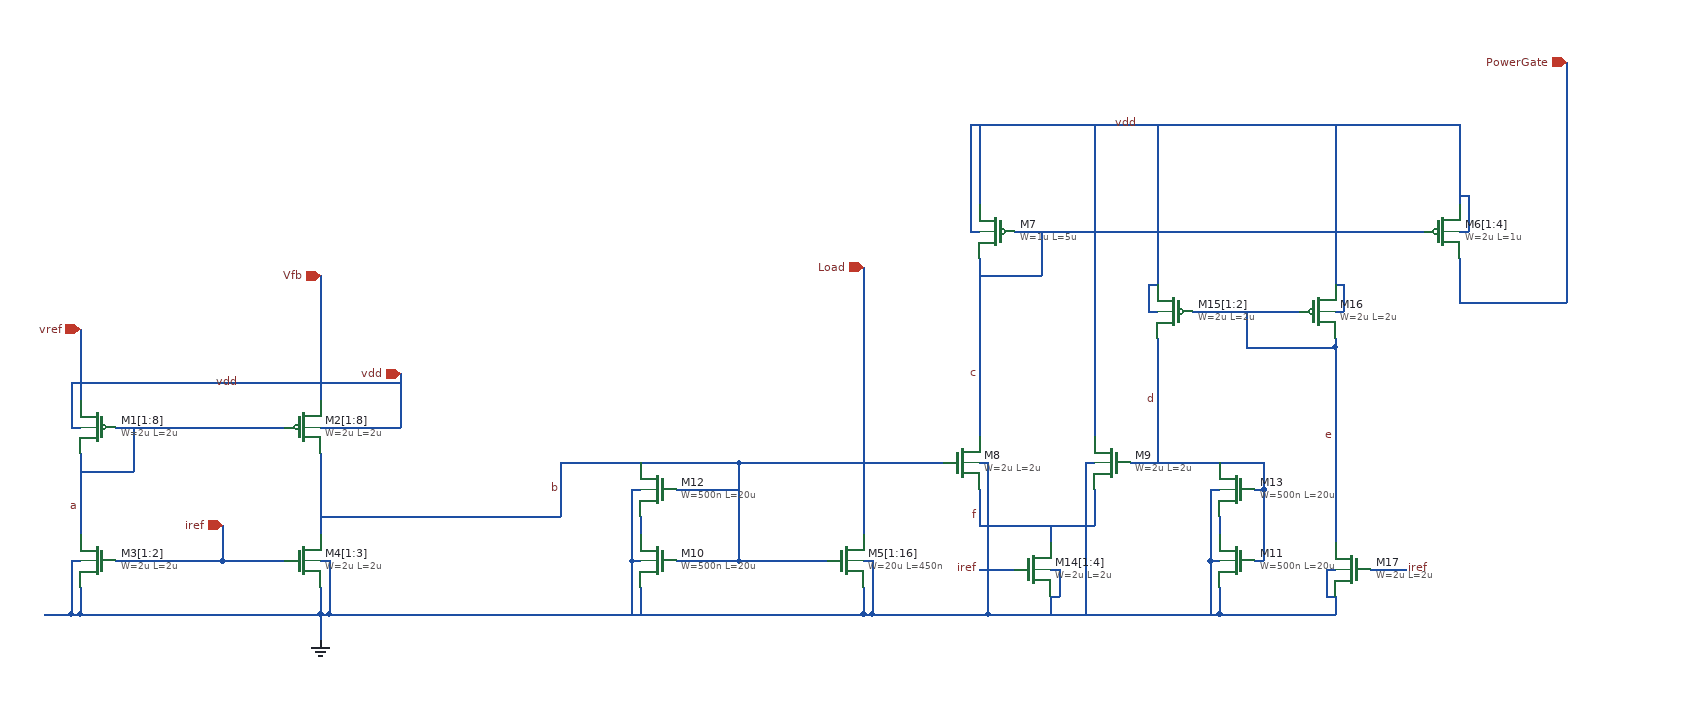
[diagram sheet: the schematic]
v {xschem version=3.4.5 file_version=1.2
}
G {}
K {}
V {}
S {}
E {}
N 370 -150 370 -120 {
lab=GND}
N 370 -180 380 -180 {
lab=GND}
N 380 -180 380 -120 {
lab=GND}
N 370 -120 380 -120 {
lab=GND}
N 370 -120 370 -90 {
lab=GND}
N 980 -150 980 -120 {
lab=GND}
N 980 -330 980 -210 {
lab=Load}
N 980 -180 990 -180 {
lab=GND}
N 990 -180 990 -120 {
lab=GND}
N 980 -120 990 -120 {
lab=GND}
N 980 -510 980 -330 {
lab=Load}
N 880 -120 980 -120 {
lab=GND}
N 840 -180 940 -180 {
lab=b}
N 840 -250 840 -180 {
lab=b}
N 260 -220 260 -180 {
lab=iref}
N 370 -250 370 -210 {
lab=b}
N 370 -300 370 -250 {
lab=b}
N 370 -330 380 -330 {
lab=vdd}
N 380 -330 460 -330 {
lab=vdd}
N 260 -180 330 -180 {
lab=iref}
N 100 -150 100 -120 {
lab=GND}
N 90 -180 100 -180 {
lab=GND}
N 90 -180 90 -120 {
lab=GND}
N 90 -120 100 -120 {
lab=GND}
N 100 -250 100 -210 {
lab=a}
N 100 -300 100 -250 {
lab=a}
N 90 -330 100 -330 {
lab=vdd}
N 140 -330 330 -330 {
lab=a}
N 140 -180 260 -180 {
lab=iref}
N 100 -120 370 -120 {
lab=GND}
N 90 -380 90 -330 {
lab=vdd}
N 90 -380 460 -380 {
lab=vdd}
N 100 -280 160 -280 {
lab=a}
N 160 -330 160 -280 {
lab=a}
N 460 -390 460 -330 {
lab=vdd}
N 370 -500 370 -360 {
lab=Vfb}
N 1770 -740 1770 -520 {
lab=PowerGate}
N 380 -120 880 -120 {
lab=GND}
N 1650 -550 1660 -550 {
lab=vdd}
N 1110 -290 1120 -290 {
lab=f}
N 1100 -550 1110 -550 {
lab=vdd}
N 1100 -600 1100 -550 {
lab=vdd}
N 1650 -600 1650 -580 {
lab=vdd}
N 1770 -520 1770 -470 {
lab=PowerGate}
N 1110 -520 1110 -430 {
lab=c}
N 1110 -610 1110 -580 {
lab=vdd}
N 1100 -670 1100 -600 {
lab=vdd}
N 1370 -670 1650 -670 {
lab=vdd}
N 1650 -670 1650 -600 {
lab=vdd}
N 1660 -590 1660 -550 {
lab=vdd}
N 1650 -590 1660 -590 {
lab=vdd}
N 990 -120 1110 -120 {
lab=GND}
N 1110 -120 1120 -120 {
lab=GND}
N 1110 -430 1110 -360 {
lab=c}
N 1120 -120 1310 -120 {
lab=GND}
N 1190 -140 1190 -120 {
lab=GND}
N 1110 -670 1110 -610 {
lab=vdd}
N 720 -180 730 -180 {
lab=GND}
N 720 -180 720 -120 {
lab=GND}
N 730 -150 730 -120 {
lab=GND}
N 770 -180 840 -180 {
lab=b}
N 730 -230 730 -210 {
lab=#net1}
N 720 -260 720 -180 {
lab=GND}
N 720 -260 730 -260 {
lab=GND}
N 730 -290 840 -290 {
lab=b}
N 840 -290 840 -250 {
lab=b}
N 770 -260 840 -260 {
lab=b}
N 840 -290 1050 -290 {
lab=b}
N 370 -230 640 -230 {
lab=b}
N 640 -290 640 -230 {
lab=b}
N 640 -290 730 -290 {
lab=b}
N 1650 -520 1650 -480 {
lab=PowerGate}
N 1650 -480 1650 -470 {
lab=PowerGate}
N 1650 -470 1770 -470 {
lab=PowerGate}
N 1110 -500 1180 -500 {
lab=c}
N 1180 -550 1180 -500 {
lab=c}
N 1120 -290 1120 -260 {
lab=f}
N 1050 -290 1070 -290 {
lab=b}
N 1110 -360 1110 -320 {
lab=c}
N 1190 -220 1190 -200 {
lab=f}
N 1110 -220 1140 -220 {
lab=f}
N 1110 -260 1110 -220 {
lab=f}
N 1230 -290 1240 -290 {
lab=f}
N 1230 -290 1230 -260 {
lab=f}
N 1240 -360 1240 -320 {
lab=vdd}
N 1240 -260 1240 -220 {
lab=f}
N 1140 -220 1240 -220 {
lab=f}
N 1240 -670 1240 -360 {
lab=vdd}
N 1370 -180 1380 -180 {
lab=GND}
N 1370 -180 1370 -120 {
lab=GND}
N 1380 -150 1380 -120 {
lab=GND}
N 1380 -230 1380 -210 {
lab=#net2}
N 1370 -260 1370 -180 {
lab=GND}
N 1370 -260 1380 -260 {
lab=GND}
N 1310 -120 1380 -120 {
lab=GND}
N 1420 -180 1430 -180 {
lab=d}
N 1430 -260 1430 -180 {
lab=d}
N 1420 -260 1430 -260 {
lab=d}
N 1420 -260 1430 -260 {
lab=d}
N 1430 -290 1430 -260 {
lab=d}
N 1280 -290 1430 -290 {
lab=d}
N 1310 -360 1310 -290 {
lab=d}
N 1190 -170 1200 -170 {
lab=GND}
N 1200 -170 1200 -140 {
lab=GND}
N 1190 -140 1200 -140 {
lab=GND}
N 1110 -170 1150 -170 {
lab=iref}
N 1100 -670 1370 -670 {
lab=vdd}
N 1150 -550 1610 -550 {
lab=c}
N 1310 -430 1310 -360 {
lab=d}
N 1350 -460 1470 -460 {
lab=e}
N 1300 -460 1310 -460 {
lab=vdd}
N 1300 -490 1300 -460 {
lab=vdd}
N 1300 -490 1310 -490 {
lab=vdd}
N 1310 -670 1310 -490 {
lab=vdd}
N 1510 -670 1510 -490 {
lab=vdd}
N 1510 -460 1520 -460 {
lab=vdd}
N 1520 -490 1520 -460 {
lab=vdd}
N 1510 -490 1520 -490 {
lab=vdd}
N 1410 -460 1410 -420 {
lab=e}
N 1410 -420 1510 -420 {
lab=e}
N 1510 -430 1510 -420 {
lab=e}
N 1510 -140 1510 -120 {
lab=GND}
N 1500 -170 1510 -170 {
lab=GND}
N 1500 -170 1500 -140 {
lab=GND}
N 1500 -140 1510 -140 {
lab=GND}
N 1550 -170 1590 -170 {
lab=iref}
N 1380 -120 1510 -120 {
lab=GND}
N 1510 -420 1510 -200 {
lab=e}
N 60 -120 90 -120 {
lab=GND}
N 100 -440 100 -360 {
lab=vref}
N 1120 -260 1120 -120 {}
N 1230 -260 1230 -120 {}
C {symbols/pfet_03v3.sym} 350 -330 0 0 {name=M2[1:8]
L=2u
W=2u
nf=1
m=1
ad="'int((nf+1)/2) * W/nf * 0.18u'"
pd="'2*int((nf+1)/2) * (W/nf + 0.18u)'"
as="'int((nf+2)/2) * W/nf * 0.18u'"
ps="'2*int((nf+2)/2) * (W/nf + 0.18u)'"
nrd="'0.18u / W'" nrs="'0.18u / W'"
sa=0 sb=0 sd=0
model=pfet_03v3
spiceprefix=X
}
C {symbols/nfet_03v3.sym} 350 -180 0 0 {name=M4[1:3]
L=2u
W=2u
nf=1
m=1
ad="'int((nf+1)/2) * W/nf * 0.18u'"
pd="'2*int((nf+1)/2) * (W/nf + 0.18u)'"
as="'int((nf+2)/2) * W/nf * 0.18u'"
ps="'2*int((nf+2)/2) * (W/nf + 0.18u)'"
nrd="'0.18u / W'" nrs="'0.18u / W'"
sa=0 sb=0 sd=0
model=nfet_03v3
spiceprefix=X
}
C {devices/gnd.sym} 370 -90 0 0 {name=l1 lab=GND}
C {devices/iopin.sym} 100 -440 3 0 {name=p3 lab=vref
}
C {devices/iopin.sym} 260 -220 2 0 {name=p4 lab=iref
}
C {devices/iopin.sym} 460 -390 3 0 {name=p5 lab=vdd
}
C {devices/iopin.sym} 980 -510 3 0 {name=p1 lab=Load
}
C {symbols/nfet_03v3.sym} 960 -180 0 0 {name=M5[1:16]
L=450n
W=20u
nf=1
m=1
ad="'int((nf+1)/2) * W/nf * 0.18u'"
pd="'2*int((nf+1)/2) * (W/nf + 0.18u)'"
as="'int((nf+2)/2) * W/nf * 0.18u'"
ps="'2*int((nf+2)/2) * (W/nf + 0.18u)'"
nrd="'0.18u / W'" nrs="'0.18u / W'"
sa=0 sb=0 sd=0
model=nfet_03v3
spiceprefix=X
}
C {symbols/pfet_03v3.sym} 120 -330 0 1 {name=M1[1:8]
L=2u
W=2u
nf=1
m=1
ad="'int((nf+1)/2) * W/nf * 0.18u'"
pd="'2*int((nf+1)/2) * (W/nf + 0.18u)'"
as="'int((nf+2)/2) * W/nf * 0.18u'"
ps="'2*int((nf+2)/2) * (W/nf + 0.18u)'"
nrd="'0.18u / W'" nrs="'0.18u / W'"
sa=0 sb=0 sd=0
model=pfet_03v3
spiceprefix=X
}
C {symbols/nfet_03v3.sym} 120 -180 0 1 {name=M3[1:2]
L=2u
W=2u
nf=1
m=1
ad="'int((nf+1)/2) * W/nf * 0.18u'"
pd="'2*int((nf+1)/2) * (W/nf + 0.18u)'"
as="'int((nf+2)/2) * W/nf * 0.18u'"
ps="'2*int((nf+2)/2) * (W/nf + 0.18u)'"
nrd="'0.18u / W'" nrs="'0.18u / W'"
sa=0 sb=0 sd=0
model=nfet_03v3
spiceprefix=X
}
C {devices/iopin.sym} 370 -500 3 0 {name=p2 lab=Vfb
}
C {devices/iopin.sym} 1770 -740 3 0 {name=p6 lab=PowerGate
}
C {devices/lab_wire.sym} 280 -380 0 0 {name=p7 sig_type=std_logic lab=vdd}
C {symbols/pfet_03v3.sym} 1630 -550 0 0 {name=M6[1:4]
L=1u
W=2u
nf=1
m=1
ad="'int((nf+1)/2) * W/nf * 0.18u'"
pd="'2*int((nf+1)/2) * (W/nf + 0.18u)'"
as="'int((nf+2)/2) * W/nf * 0.18u'"
ps="'2*int((nf+2)/2) * (W/nf + 0.18u)'"
nrd="'0.18u / W'" nrs="'0.18u / W'"
sa=0 sb=0 sd=0
model=pfet_03v3
spiceprefix=X
}
C {symbols/pfet_03v3.sym} 1130 -550 0 1 {name=M7
L=5u
W=1u
nf=1
m=1
ad="'int((nf+1)/2) * W/nf * 0.18u'"
pd="'2*int((nf+1)/2) * (W/nf + 0.18u)'"
as="'int((nf+2)/2) * W/nf * 0.18u'"
ps="'2*int((nf+2)/2) * (W/nf + 0.18u)'"
nrd="'0.18u / W'" nrs="'0.18u / W'"
sa=0 sb=0 sd=0
model=pfet_03v3
spiceprefix=X
}
C {symbols/nfet_03v3.sym} 1090 -290 0 0 {name=M8
L=2u
W=2u
nf=1
m=1
ad="'int((nf+1)/2) * W/nf * 0.18u'"
pd="'2*int((nf+1)/2) * (W/nf + 0.18u)'"
as="'int((nf+2)/2) * W/nf * 0.18u'"
ps="'2*int((nf+2)/2) * (W/nf + 0.18u)'"
nrd="'0.18u / W'" nrs="'0.18u / W'"
sa=0 sb=0 sd=0
model=nfet_03v3
spiceprefix=X
}
C {devices/lab_wire.sym} 1290 -670 0 0 {name=p8 sig_type=std_logic lab=vdd}
C {symbols/nfet_03v3.sym} 750 -180 0 1 {name=M10
L=20u
W=500n
nf=1
m=1
ad="'int((nf+1)/2) * W/nf * 0.18u'"
pd="'2*int((nf+1)/2) * (W/nf + 0.18u)'"
as="'int((nf+2)/2) * W/nf * 0.18u'"
ps="'2*int((nf+2)/2) * (W/nf + 0.18u)'"
nrd="'0.18u / W'" nrs="'0.18u / W'"
sa=0 sb=0 sd=0
model=nfet_03v3
spiceprefix=X
}
C {symbols/nfet_03v3.sym} 750 -260 0 1 {name=M12
L=20u
W=500n
nf=1
m=1
ad="'int((nf+1)/2) * W/nf * 0.18u'"
pd="'2*int((nf+1)/2) * (W/nf + 0.18u)'"
as="'int((nf+2)/2) * W/nf * 0.18u'"
ps="'2*int((nf+2)/2) * (W/nf + 0.18u)'"
nrd="'0.18u / W'" nrs="'0.18u / W'"
sa=0 sb=0 sd=0
model=nfet_03v3
spiceprefix=X
}
C {symbols/nfet_03v3.sym} 1260 -290 0 1 {name=M9
L=2u
W=2u
nf=1
m=1
ad="'int((nf+1)/2) * W/nf * 0.18u'"
pd="'2*int((nf+1)/2) * (W/nf + 0.18u)'"
as="'int((nf+2)/2) * W/nf * 0.18u'"
ps="'2*int((nf+2)/2) * (W/nf + 0.18u)'"
nrd="'0.18u / W'" nrs="'0.18u / W'"
sa=0 sb=0 sd=0
model=nfet_03v3
spiceprefix=X
}
C {symbols/nfet_03v3.sym} 1400 -180 0 1 {name=M11
L=20u
W=500n
nf=1
m=1
ad="'int((nf+1)/2) * W/nf * 0.18u'"
pd="'2*int((nf+1)/2) * (W/nf + 0.18u)'"
as="'int((nf+2)/2) * W/nf * 0.18u'"
ps="'2*int((nf+2)/2) * (W/nf + 0.18u)'"
nrd="'0.18u / W'" nrs="'0.18u / W'"
sa=0 sb=0 sd=0
model=nfet_03v3
spiceprefix=X
}
C {symbols/nfet_03v3.sym} 1400 -260 0 1 {name=M13
L=20u
W=500n
nf=1
m=1
ad="'int((nf+1)/2) * W/nf * 0.18u'"
pd="'2*int((nf+1)/2) * (W/nf + 0.18u)'"
as="'int((nf+2)/2) * W/nf * 0.18u'"
ps="'2*int((nf+2)/2) * (W/nf + 0.18u)'"
nrd="'0.18u / W'" nrs="'0.18u / W'"
sa=0 sb=0 sd=0
model=nfet_03v3
spiceprefix=X
}
C {symbols/nfet_03v3.sym} 1170 -170 0 0 {name=M14[1:4]
L=2u
W=2u
nf=1
m=1
ad="'int((nf+1)/2) * W/nf * 0.18u'"
pd="'2*int((nf+1)/2) * (W/nf + 0.18u)'"
as="'int((nf+2)/2) * W/nf * 0.18u'"
ps="'2*int((nf+2)/2) * (W/nf + 0.18u)'"
nrd="'0.18u / W'" nrs="'0.18u / W'"
sa=0 sb=0 sd=0
model=nfet_03v3
spiceprefix=X
}
C {devices/lab_wire.sym} 1110 -170 0 0 {name=p9 sig_type=std_logic lab=iref}
C {symbols/pfet_03v3.sym} 1330 -460 0 1 {name=M15[1:2]
L=2u
W=2u
nf=1
m=1
ad="'int((nf+1)/2) * W/nf * 0.18u'"
pd="'2*int((nf+1)/2) * (W/nf + 0.18u)'"
as="'int((nf+2)/2) * W/nf * 0.18u'"
ps="'2*int((nf+2)/2) * (W/nf + 0.18u)'"
nrd="'0.18u / W'" nrs="'0.18u / W'"
sa=0 sb=0 sd=0
model=pfet_03v3
spiceprefix=X
}
C {symbols/pfet_03v3.sym} 1490 -460 0 0 {name=M16
L=2u
W=2u
nf=1
m=1
ad="'int((nf+1)/2) * W/nf * 0.18u'"
pd="'2*int((nf+1)/2) * (W/nf + 0.18u)'"
as="'int((nf+2)/2) * W/nf * 0.18u'"
ps="'2*int((nf+2)/2) * (W/nf + 0.18u)'"
nrd="'0.18u / W'" nrs="'0.18u / W'"
sa=0 sb=0 sd=0
model=pfet_03v3
spiceprefix=X
}
C {symbols/nfet_03v3.sym} 1530 -170 0 1 {name=M17
L=2u
W=2u
nf=1
m=1
ad="'int((nf+1)/2) * W/nf * 0.18u'"
pd="'2*int((nf+1)/2) * (W/nf + 0.18u)'"
as="'int((nf+2)/2) * W/nf * 0.18u'"
ps="'2*int((nf+2)/2) * (W/nf + 0.18u)'"
nrd="'0.18u / W'" nrs="'0.18u / W'"
sa=0 sb=0 sd=0
model=nfet_03v3
spiceprefix=X
}
C {devices/lab_wire.sym} 1590 -170 0 1 {name=p10 sig_type=std_logic lab=iref}
C {devices/lab_pin.sym} 100 -240 0 0 {name=p11 sig_type=std_logic lab=a}
C {devices/lab_pin.sym} 640 -260 0 0 {name=p12 sig_type=std_logic lab=b}
C {devices/lab_pin.sym} 1110 -390 0 0 {name=p13 sig_type=std_logic lab=c}
C {devices/lab_pin.sym} 1310 -360 0 0 {name=p14 sig_type=std_logic lab=d}
C {devices/lab_pin.sym} 1510 -320 0 0 {name=p15 sig_type=std_logic lab=e
}
C {devices/lab_pin.sym} 1110 -230 0 0 {name=p16 sig_type=std_logic lab=f}
